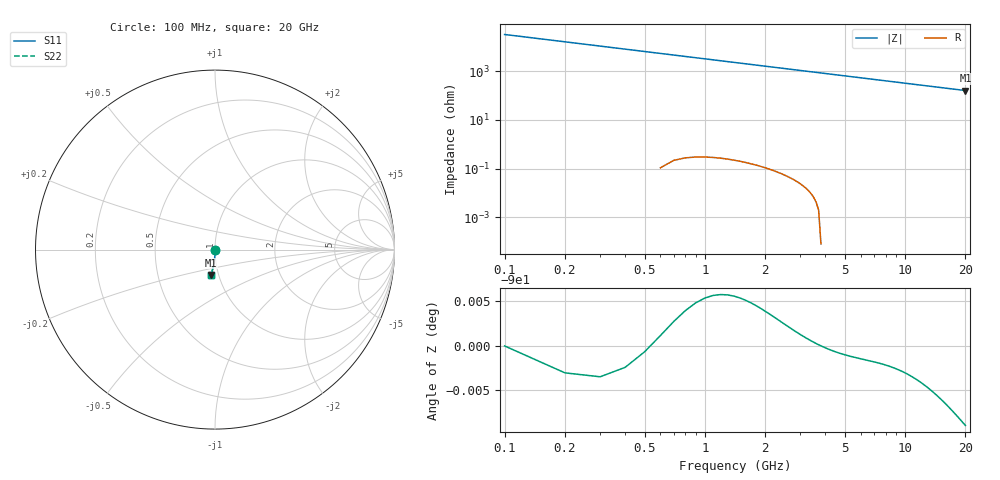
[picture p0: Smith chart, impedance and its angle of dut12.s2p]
! Touchstone file exported from HFSS 2026.1.0
!  File:  C:/ffzhzh/LocalFiles/Ansys_Project_Files/temp_test_TSV_12_1782978225_6388.aedt
!  Generated:  03:44:56 PM Jul  2, 2026
!  Design:  TSV
!  Project:  temp_test_TSV_12_1782978225_6388
! Variables:
!  h_bsmrdl = 2um
!  h_ox = 20um
!  h_rdl = 5um
!  h_sub = 52.46um
!  h_tmrdl = 5um
!  h_tsv = 52.46um
!  h_via = 3um
!  l_bsmrdl = 300um
!  l_sub = 424.92um
!  l_tmrdl = 200um
!  m_sub = 200um
!  pitch = 26.36um
!  r_tsv = 12.46um
!  s_tmrdl = 10um
!  w_bsmrdl = 18um
!  w_sub = 500um
!  w_tmrdl = 12um
!  x_tsv_center1 = 206um
!  x_tsv_center2 = 524um
!  x_tsv_center3 = 736um
!  x_tsv_center4 = 1054um
!  x_tsv_center5 = 1266um
!  x_tsv_center6 = 1584um
# GHz S MA R 50.000000
! Terminal data exported
! Port[1] = TSV1_1_T1
! Port[2] = TSV1_1_T2
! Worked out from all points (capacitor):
!   200 points, 100 MHz to 20 GHz, reference 50 ohm
!   read as one part in shunt: C = 49.9 fF near 200 MHz
!   lowest |Z| = 160 ohm at 20 GHz (marker M1)
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0.1  0.0006723 -82.6  0.9999 -0.1  0.9999 -0.1  0.0006723 -82.6
! Gamma 0 0 0 0
! Port Impedance 50 0 50 0
0.2  0.001343 -85.6  0.9999 -0.1  0.9999 -0.1  0.001343 -85.6
0.3  0.002025 -86.4  0.9999 -0.2  0.9999 -0.2  0.002025 -86.4
0.4  0.002718 -86.8  0.9998 -0.2  0.9998 -0.2  0.002718 -86.8
0.5  0.003418 -87.0  0.9998 -0.3  0.9998 -0.3  0.003418 -87.0
0.7  0.004837 -87.4  0.9997 -0.4  0.9997 -0.4  0.004837 -87.4
0.8  0.005551 -87.6  0.9997 -0.4  0.9997 -0.4  0.005551 -87.6
1  0.006983 -88.0  0.9997 -0.5  0.9997 -0.5  0.006983 -88.0
1.2  0.008417 -88.3  0.9996 -0.6  0.9996 -0.6  0.008417 -88.3
1.4  0.009851 -88.6  0.9996 -0.7  0.9996 -0.7  0.009851 -88.6
1.7  0.012 -89.0  0.9995 -0.8  0.9995 -0.8  0.012 -89.0
2  0.01415 -89.3  0.9995 -1.0  0.9995 -1.0  0.01415 -89.3
2.7  0.01917 -89.9  0.9993 -1.3  0.9993 -1.3  0.01917 -89.9
3.5  0.0249 -90.5  0.9992 -1.7  0.9992 -1.7  0.0249 -90.5
4.2  0.02993 -90.9  0.999 -2.1  0.999 -2.1  0.02993 -90.9
5  0.03568 -91.4  0.9987 -2.4  0.9987 -2.4  0.03568 -91.4
6.8  0.04862 -92.4  0.998 -3.3  0.998 -3.3  0.04862 -92.4
8.3  0.05941 -93.2  0.9973 -4.0  0.9973 -4.0  0.05941 -93.2
10.1  0.07233 -94.1  0.9964 -4.9  0.9964 -4.9  0.07233 -94.1
13.4  0.09591 -95.8  0.9942 -6.5  0.9942 -6.5  0.09591 -95.8
16.7  0.1193 -97.4  0.9915 -8.1  0.9915 -8.1  0.1193 -97.4
20  0.1426 -99.0  0.9883 -9.6  0.9883 -9.6  0.1426 -99.0
